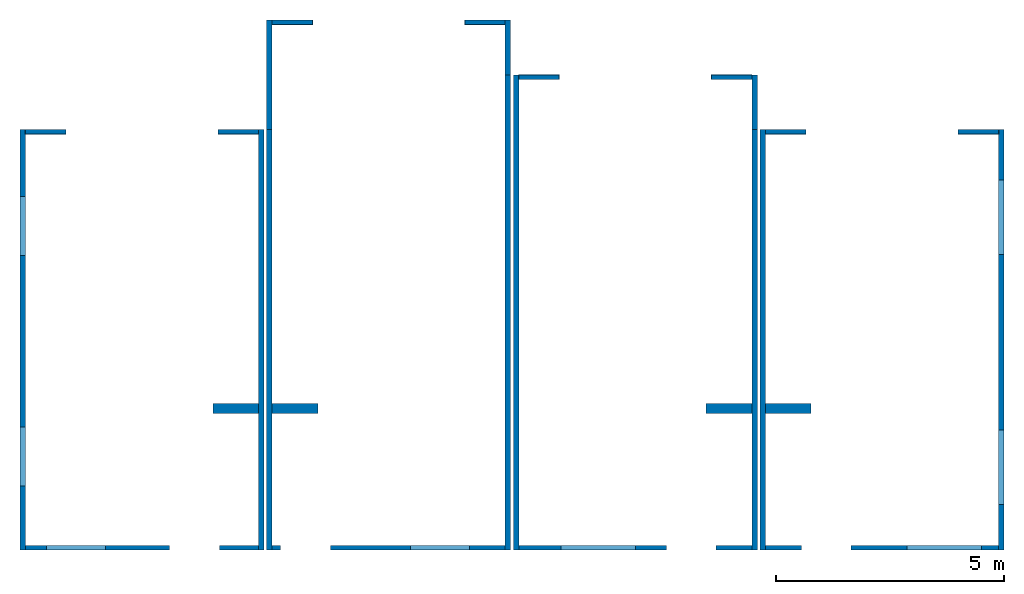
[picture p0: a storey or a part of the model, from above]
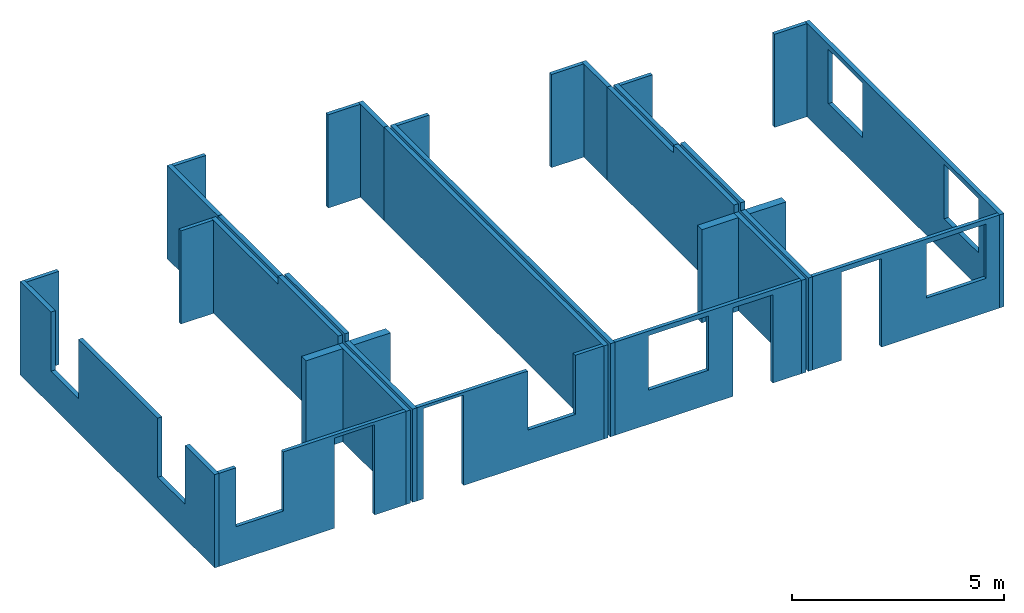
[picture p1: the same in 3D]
Properties of the parts of a building model (IFC2X3)

# File
Description: ViewDefinition [CoordinationView_V2.0]
File name: Voorbeeldproject Aanlevering BIM calduran_v2.ifc (Edited by simplebim 6.1 SR4)
Time: 2021-08-24T09:26:27
Written by: The EXPRESS Data Manager Version 5.02.0100.07 : 28 Aug 2013
Made in: 20190412_1200(x64) - Exporter 20.3.1.0 - Alternate UI 20.3.1.0 .Edited by BimVison - IFC Split

# IfcProject, 0001
LongName: Project Name; Phase: Project Status

# IfcSite, Harderwijk
RefLatitude: 42, 21, 29, 879998; RefLongitude: -71, -3, -37, -79998; RefElevation: 0 mm
ePset_ModelInfo - ModelName: Voorbeeldproject Aanlevering BIM calduran_v2.ifc; Timestamp: 2021-08-24T09:26:27
Text - TemplateVersie: bt_revit_template.rte : 20-06-2019 R2016 ©RB
Identity Data - Building Name: 763_Blok 01
Other - SiteName: Harderwijk; Category: Project Information; Project Number: 4 woningen; Client Name: Calduran b.v.; Project Address: 4 woningen te Harderwijk; Extensions.Parameters: n.v.t.; Project Issue Date: n.v.t.; Project Name: n.v.t.
Pset_ProductRequirements - Category: Project Information

# IfcBuilding
ePset_ModelInfo - ModelName: Voorbeeldproject Aanlevering BIM calduran_v2.ifc; Timestamp: 2021-08-24T09:26:27
Pset_BuildingCommon - NumberOfStoreys: 4
Text - TemplateVersie: bt_revit_template.rte : 20-06-2019 R2016 ©RB
Identity Data - Building Name: 763_Blok 01
Other - SiteName: Harderwijk; Category: Project Information; Project Number: 4 woningen; Client Name: Calduran b.v.; Project Address: 4 woningen te Harderwijk; Project Name: n.v.t.; Extensions.Parameters: n.v.t.; Project Issue Date: n.v.t.
Pset_ProductRequirements - Category: Project Information

# IfcBuildingStorey: Level:8mm Head (3)
ePset_ModelInfo - ModelName: Voorbeeldproject Aanlevering BIM calduran_v2.ifc; Timestamp: 2021-08-24T09:26:27
Dimensions - Computation Height: 0 mm
Identity Data(Type) - Type Name: hulp-level tbv Vloerpeil Niveau
Identity Data - Building Story: yes; Structural: no
Graphics(Type) - Color: 255; Symbol at End 1 Default: no; Symbol at End 2 Default: no; Line Weight: 1; Line Pattern: bt_hoogtelijn; Symbol: bt_hoogtelijnen: Hoogtemaat_Boven
Constraints(Type) - Elevation Base: Project Base Point
Pset_ProductRequirements - Category: Levels
Other(Type) - Category: Levels; Family Name: Level
Other - Family: Level: hulp-level tbv Vloerpeil Niveau; Family and Type: Level: hulp-level tbv Vloerpeil Niveau; Type: Level: hulp-level tbv Vloerpeil Niveau; Type Id: Level: hulp-level tbv Vloerpeil Niveau; Category: Levels
Name | LongName = Pset_AirSideSystemInformation, Name = Identity Data, Name = Pset_ProductRequirements, Name | Elevation (mm) = Constraints, Elevation (mm)
00 begane grond | 00 begane grond | 0
01 eerste verdieping | 01 eerste verdieping | 2920
02 tweede verdieping | 02 tweede verdieping | 5840

# IfcGrid (3)
ePset_ModelInfo - ModelName: Voorbeeldproject Aanlevering BIM calduran_v2.ifc; Timestamp: 2021-08-24T09:26:27
Name | In
 | 01 eerste verdieping
 | 00 begane grond
 | 02 tweede verdieping

# IfcOpeningElement: Opening (57)
ePset_ModelInfo - ModelName: Voorbeeldproject Aanlevering BIM calduran_v2.ifc; Timestamp: 2021-08-24T09:26:27
Name (Basic Wall:...) | In
2 x 21_kalkzandsteen element_CS12_100mm:1181608 | 00 begane grond
2 x 21_kalkzandsteen element_CS12_120mm:1090852 | 01 eerste verdieping
2 x 21_kalkzandsteen element_CS12_100mm:1182037 | 01 eerste verdieping
8 x 22_kalkzandsteen element_CS12_120mm:463458 | 00 begane grond | Classification: 22.22 binnenwanden; constructief, spouwwanden (NL/SfB)
2 x 21_kalkzandsteen element_CS12_120mm:1090762 | 00 begane grond
2 x 21_kalkzandsteen element_CS12_120mm:1090776 | 00 begane grond
8 x 22_kalkzandsteen element_CS12_120mm:463458 | 01 eerste verdieping | Classification: 22.22 binnenwanden; constructief, spouwwanden (NL/SfB)
2 x 21_kalkzandsteen element_CS12_100mm:1179562 | 00 begane grond
2 x 21_kalkzandsteen element_CS12_120mm:1090848 | 01 eerste verdieping
22_kalkzandsteen element_CS12_120mm:463458 | 02 tweede verdieping | Classification: 22.22 binnenwanden; constructief, spouwwanden (NL/SfB)
2 x 21_kalkzandsteen element_CS12_100mm:1182137 | 00 begane grond
21_kalkzandsteen element_CS12_120mm:1091307 | 02 tweede verdieping
2 x 21_kalkzandsteen element_CS12_100mm:1180744 | 01 eerste verdieping
21_kalkzandsteen element_CS12_100mm:1179981 | 00 begane grond
2 x 21_kalkzandsteen element_CS12_100mm:1180970 | 01 eerste verdieping
2 x 21_kalkzandsteen element_CS12_100mm:1181490 | 01 eerste verdieping
2 x 21_kalkzandsteen element_CS12_100mm:1181492 | 01 eerste verdieping
21_kalkzandsteen element_CS12_100mm:1181610 | 00 begane grond
2 x 21_kalkzandsteen element_CS12_100mm:1181998 | 01 eerste verdieping
21_kalkzandsteen element_CS12_100mm:1182139 | 00 begane grond
2 x 21_kalkzandsteen element_CS12_100mm:1182144 | 00 begane grond
21_kalkzandsteen element_CS12_100mm:1182146 | 00 begane grond
2 x 21_kalkzandsteen element_CS12_100mm:1182415 | 01 eerste verdieping
21_kalkzandsteen element_CS12_100mm:1182474 | 01 eerste verdieping
21_kalkzandsteen element_CS12_100mm:1183339 | 02 tweede verdieping
21_kalkzandsteen element_CS12_100mm:1184081 | 02 tweede verdieping
21_kalkzandsteen element_CS12_100mm:1179616 | 02 tweede verdieping | Classification: 21.12 buitenwanden; niet constructief, spouwwanden (NL/SfB)
21_kalkzandsteen element_CS12_100mm:1184943 | 02 tweede verdieping

# IfcWallStandardCase: 21_kalkzandsteen element_CS12_100mm (19)
Type - PredefinedType: STANDARD; Material: kalkzandsteen_CS12 100 mm
Type - Analytical Properties(Type) - Absorptance: 0.1; Roughness: 1
Type - Construction(Type) - Function: Exterior; Width: 100 mm; Wrapping at Inserts: Do not wrap
Type - Graphics(Type) - Coarse Scale Fill Color: 0; Coarse Scale Fill Pattern: Kalkzandsteen
Type - Identity Data(Type) - Assembly Code: 21.12; Assembly Description: buitenwanden; niet constructief, spouwwanden; Description: kalkzandsteen d=100 CS12; FireRatingR: 0 min.; LoadBearing: no; Sterkteklasse: CS12; Type Mark: KZS 100 (CS12); Type Name: 21_kalkzandsteen element_CS12_100mm; Type Comments: niet dragend
Type - Materials and Finishes(Type) - Structural Material: kalkzandsteen_CS12
Type - Other(Type) - Category: Walls; Family Name: Basic Wall
Classification: 21.12 buitenwanden; niet constructief, spouwwanden (NL/SfB)
ePset_ModelInfo - ModelName: Voorbeeldproject Aanlevering BIM calduran_v2.ifc; Timestamp: 2021-08-24T09:26:27
Pset_WallCommon - Reference: 21_kalkzandsteen element_CS12_100mm; LoadBearing: no; IsExternal: yes; ExtendToStructure: no
Phasing - Phase Created: 2. nieuwbouw
Pset_ElementShading - Roughness: 304.8 mm
Pset_QuantityTakeOff - Reference: 21_kalkzandsteen element_CS12_100mm
Constraints - Base Offset: -70 mm; Base Extension Distance: 0 mm; Base is Attached: no; Related to Mass: no; Room Bounding: yes; Top Extension Distance: 0 mm; Top is Attached: no; Location Line: Core Face: Exterior
Identity Data - IsExternal: yes
Other - Type Id: Basic Wall: 21_kalkzandsteen element_CS12_100mm; Family and Type: Basic Wall: 21_kalkzandsteen element_CS12_100mm; Type: Basic Wall: 21_kalkzandsteen element_CS12_100mm; Family: Basic Wall: 21_kalkzandsteen element_CS12_100mm; Category: Walls
Pset_ProductRequirements - Category: Walls
Structural - Structural: yes; Enable Analytical Model: yes; Structural Usage: Bearing; Rebar Cover - Other Faces: Rebar Cover Settings: Rebar Cover 1; Rebar Cover - Exterior Face: Rebar Cover Settings: Rebar Cover 1; Rebar Cover - Interior Face: Rebar Cover Settings: Rebar Cover 1
Calduran - Naam: Basic Wall: 21_kalkzandsteen element_CS12_100mm; Sterkteklasse: CS12; NL-Sfb omschrijving: buitenwanden; niet constructief, spouwwanden; NL-Sfb: 21.12; IsExternal: yes; LoadBearing: yes; Material: kalkzandsteen_CS12; Breedte: 100 mm
Pset_ReinforcementBarPitchOfWall - Description: kalkzandsteen d=100 CS12
Pset_Draughting - Red: 255; Green: 248; Blue: 220
BaseQuantities - Width: 100 mm
Name (Basic Wall:21_kalkzandsteen element_CS12_100mm:...) | In | Dimensions, Length (mm) = Lengte (mm) = BaseQuantities, Length (mm) | Dimensions, Volume (m3) = Calduran, Volume (m3) = NetVolume (m3) | Area (mm2) = Oppervlak (mm2) = NetSideArea (mm2) | Top Offset (mm) | Unconnected Height (mm) = Hoogte (mm) | Base Constraint = Top Constraint = Level | Identity Data, Bouwlaag = Calduran, Bouwlaag | GrossFootprintArea (mm2) | Height (mm)
1181608 | 00 begane grond | 5100 | 0.839766 | 8397660 | 2620 | 2690 | Level: 00 begane grond | 00 begane grond | 510000 | 2690
1182037 | 01 eerste verdieping | 5100 | 0.958892 | 9588920 | 2620 | 2690 | Level: 01 eerste verdieping | 01 eerste verdieping | 510000 | 2690
1179562 | 00 begane grond | 5100 | 0.86819 | 8681900 | 2620 | 2690 | Level: 00 begane grond | 00 begane grond | 510000 | 2690
1182137 | 00 begane grond | 5100 | 0.839766 | 8397660 | 2620 | 2690 | Level: 00 begane grond | 00 begane grond | 510000 | 2690
1180744 | 01 eerste verdieping | 5100 | 0.922284 | 9222840 | 2620 | 2690 | Level: 01 eerste verdieping | 01 eerste verdieping | 510000 | 2690
1179981 | 00 begane grond | 5100 | 0.475054 | 4750540 | 2620 | 2690 | Level: 00 begane grond | 00 begane grond | 510000 | 2690
1180970 | 01 eerste verdieping | 5100 | 0.958892 | 9588920 | 2620 | 2690 | Level: 01 eerste verdieping | 01 eerste verdieping | 510000 | 2690
1181490 | 01 eerste verdieping | 5100 | 0.8754 | 8754000 | 2620 | 2690 | Level: 01 eerste verdieping | 01 eerste verdieping | 510000 | 2690
1181492 | 01 eerste verdieping | 5100 | 0.958892 | 9588920 | 2620 | 2690 | Level: 01 eerste verdieping | 01 eerste verdieping | 510000 | 2690
1181610 | 00 begane grond | 5100 | 0.475054 | 4750540 | 2620 | 2690 | Level: 00 begane grond | 00 begane grond | 510000 | 2690
1181998 | 01 eerste verdieping | 5100 | 0.958892 | 9588920 | 2620 | 2690 | Level: 01 eerste verdieping | 01 eerste verdieping | 510000 | 2690
1182139 | 00 begane grond | 5100 | 0.475054 | 4750540 | 2620 | 2690 | Level: 00 begane grond | 00 begane grond | 510000 | 2690
1182144 | 00 begane grond | 5100 | 0.86819 | 8681900 | 2620 | 2690 | Level: 00 begane grond | 00 begane grond | 510000 | 2690
1182146 | 00 begane grond | 5100 | 0.475054 | 4750540 | 2620 | 2690 | Level: 00 begane grond | 00 begane grond | 510000 | 2690
1182415 | 01 eerste verdieping | 5100 | 1.06634 | 10663400 | 2620 | 2690 | Level: 01 eerste verdieping | 01 eerste verdieping | 510000 | 2690
1182474 | 01 eerste verdieping | 5100 | 1.0047 | 10047000 | 2620 | 2690 | Level: 01 eerste verdieping | 02 tweede verdieping | 510000 | 2690
1183339 | 02 tweede verdieping | 5100 | 1.05306 | 10530583 | 4090 | 4160 | Level: 02 tweede verdieping | 02 tweede verdieping | 510000 | 4154.26
1184081 | 02 tweede verdieping | 5100 | 0.981285 | 9812849 | 4090 | 4160 | Level: 02 tweede verdieping | 02 tweede verdieping | 510000 | 4154.26
1184943 | 02 tweede verdieping | 3103 | 0.707432 | 7074316 | 4090 | 4160 | Level: 02 tweede verdieping | 02 tweede verdieping | 310300 | 4186.14

# IfcWallStandardCase: 21_kalkzandsteen element_CS12_120mm (9)
Type - PredefinedType: STANDARD; Material: kalkzandsteen_CS12 120 mm
Type - Analytical Properties(Type) - Absorptance: 0.1; Roughness: 1
Type - Construction(Type) - Function: Exterior; Width: 120 mm; Wrapping at Inserts: Do not wrap
Type - Graphics(Type) - Coarse Scale Fill Color: 0; Coarse Scale Fill Pattern: Kalkzandsteen
Type - Identity Data(Type) - Assembly Code: 21.22; Assembly Description: buitenwanden; constructief, spouwwanden; Description: kalkzandsteen d=120 CS12; FireRatingR: 0 min.; LoadBearing: yes; Sterkteklasse: CS12; Type Mark: KZS 120 (CS12); Type Name: 21_kalkzandsteen element_CS12_120mm
Type - Materials and Finishes(Type) - Structural Material: kalkzandsteen_CS12
Type - Other(Type) - Category: Walls; Family Name: Basic Wall
Classification: 21.22 buitenwanden; constructief, spouwwanden (NL/SfB)
ePset_ModelInfo - ModelName: Voorbeeldproject Aanlevering BIM calduran_v2.ifc; Timestamp: 2021-08-24T09:26:27
Pset_ReinforcementBarPitchOfWall - Description: kalkzandsteen d=120 CS12
Phasing - Phase Created: 2. nieuwbouw
Constraints - Base Offset: -70 mm; Base Extension Distance: 0 mm; Base is Attached: no; Related to Mass: no; Room Bounding: yes; Top Extension Distance: 0 mm; Top is Attached: no
Pset_ElementShading - Roughness: 304.8 mm
Pset_WallCommon - Reference: 21_kalkzandsteen element_CS12_120mm; LoadBearing: yes; IsExternal: yes; ExtendToStructure: no
Other - Family and Type: Basic Wall: 21_kalkzandsteen element_CS12_120mm; Type: Basic Wall: 21_kalkzandsteen element_CS12_120mm; Type Id: Basic Wall: 21_kalkzandsteen element_CS12_120mm; Family: Basic Wall: 21_kalkzandsteen element_CS12_120mm; Category: Walls
Pset_ProductRequirements - Category: Walls
Pset_QuantityTakeOff - Reference: 21_kalkzandsteen element_CS12_120mm
Structural - Structural: yes; Enable Analytical Model: yes; Structural Usage: Bearing; Rebar Cover - Other Faces: Rebar Cover Settings: Rebar Cover 1; Rebar Cover - Exterior Face: Rebar Cover Settings: Rebar Cover 1; Rebar Cover - Interior Face: Rebar Cover Settings: Rebar Cover 1
Calduran - Sterkteklasse: CS12; Naam: Basic Wall: 21_kalkzandsteen element_CS12_120mm; IsExternal: yes; LoadBearing: yes; Material: kalkzandsteen_CS12; Breedte: 120 mm; NL-Sfb: 21.22; NL-Sfb omschrijving: buitenwanden; constructief, spouwwanden
Pset_Draughting - Red: 255; Green: 248; Blue: 220
BaseQuantities - Width: 120 mm
Name (Basic Wall:21_kalkzandsteen element_CS12_120mm:...) | In | Dimensions, Volume (m3) = Calduran, Volume (m3) = NetVolume (m3) | Dimensions, Length (mm) = Lengte (mm) = BaseQuantities, Length (mm) | Area (mm2) = Oppervlak (mm2) = NetSideArea (mm2) | Location Line | Top Offset (mm) | Unconnected Height (mm) = Hoogte (mm) | Base Constraint = Top Constraint = Level | IsExternal | Identity Data, Bouwlaag = Calduran, Bouwlaag | GrossFootprintArea (mm2) | Height (mm)
1090750 | 00 begane grond | 0.38736 | 1200 | 3228000 | Wall Centerline | 2620 | 2690 | Level: 00 begane grond | yes | 00 begane grond | 144000 | 2690
1090852 | 01 eerste verdieping | 2.43022 | 9200 | 20251840 | Wall Centerline | 2620 | 2690 | Level: 01 eerste verdieping | yes | 01 eerste verdieping | 1104000 | 2690
1090762 | 00 begane grond | 2.35482 | 9200 | 19623520 | Wall Centerline | 2620 | 2690 | Level: 00 begane grond | yes | 00 begane grond | 1104000 | 2690
1090776 | 00 begane grond | 2.44107 | 9200 | 20342280 | Wall Centerline | 2620 | 2690 | Level: 00 begane grond | yes | 00 begane grond | 1104000 | 2690
1090848 | 01 eerste verdieping | 2.33328 | 9200 | 19444000 | Wall Centerline | 2620 | 2690 | Level: 01 eerste verdieping | yes | 01 eerste verdieping | 1104000 | 2690
1091307 | 02 tweede verdieping | 2.32044 | 9200 | 19336996 | Wall Centerline | 5160 | 5230 | Level: 02 tweede verdieping | yes | 02 tweede verdieping | 1104000 | 4223.55
1194969 | 00 begane grond | 0.77472 | 2400 | 6456000 | Core Face: Exterior | 2620 | 2690 | Level: 00 begane grond |  | 00 begane grond | 288000 | 2690
1195436 | 00 begane grond | 0.38736 | 1200 | 3228000 | Wall Centerline | 2620 | 2690 | Level: 00 begane grond | yes | 00 begane grond | 144000 | 2690
1252887 | 02 tweede verdieping | 0.269636 | 1175.19 | 2246966 | Core Face: Exterior | 1842 | 1912 | Level: 02 tweede verdieping |  |  | 141023 | 1912

# IfcWallStandardCase: 22_kalkzandsteen element_CS12_120mm (18)
Type - PredefinedType: STANDARD; Material: kalkzandsteen_CS12 120 mm
Type - Analytical Properties(Type) - Absorptance: 0.1; Roughness: 1
Type - Construction(Type) - Function: Exterior; Width: 120 mm; Wrapping at Inserts: Do not wrap
Type - Graphics(Type) - Coarse Scale Fill Color: 0; Coarse Scale Fill Pattern: Kalkzandsteen
Type - Identity Data(Type) - Assembly Code: 22.22; Assembly Description: binnenwanden; constructief, spouwwanden; Description: kalkzandsteen d=120 CS12; FireRatingR: 0 min.; LoadBearing: yes; Sterkteklasse: CS12; Type Mark: KZS 120 (CS12); Type Name: 22_kalkzandsteen element_CS12_120mm
Type - Materials and Finishes(Type) - Structural Material: kalkzandsteen_CS12
Type - Other(Type) - Category: Walls; Family Name: Basic Wall
Classification: 22.22 binnenwanden; constructief, spouwwanden (NL/SfB)
ePset_ModelInfo - ModelName: Voorbeeldproject Aanlevering BIM calduran_v2.ifc; Timestamp: 2021-08-24T09:26:27
Pset_ReinforcementBarPitchOfWall - Description: kalkzandsteen d=120 CS12
Phasing - Phase Created: 2. nieuwbouw
Constraints - Base Offset: -70 mm; Location Line: Wall Centerline; Base Extension Distance: 0 mm; Base is Attached: no; Related to Mass: no; Room Bounding: yes; Top Extension Distance: 0 mm; Top is Attached: no
Pset_WallCommon - LoadBearing: yes; IsExternal: no; ExtendToStructure: no; Reference: 22_kalkzandsteen element_CS12_120mm
Pset_ElementShading - Roughness: 304.8 mm
Calduran - NL-Sfb: 22.22; Sterkteklasse: CS12; Naam: Basic Wall: 22_kalkzandsteen element_CS12_120mm; NL-Sfb omschrijving: binnenwanden; constructief, spouwwanden; LoadBearing: yes; IsExternal: no; Material: kalkzandsteen_CS12; Breedte: 120 mm
Pset_QuantityTakeOff - Reference: 22_kalkzandsteen element_CS12_120mm
Other - Family: Basic Wall: 22_kalkzandsteen element_CS12_120mm; Type Id: Basic Wall: 22_kalkzandsteen element_CS12_120mm; Type: Basic Wall: 22_kalkzandsteen element_CS12_120mm; Family and Type: Basic Wall: 22_kalkzandsteen element_CS12_120mm; Category: Walls
Pset_ProductRequirements - Category: Walls
Structural - Structural: yes; Enable Analytical Model: yes; Structural Usage: Bearing; Rebar Cover - Other Faces: Rebar Cover Settings: Rebar Cover 1; Rebar Cover - Exterior Face: Rebar Cover Settings: Rebar Cover 1; Rebar Cover - Interior Face: Rebar Cover Settings: Rebar Cover 1
Identity Data - IsExternal: no
Pset_Draughting - Red: 255; Green: 248; Blue: 220
BaseQuantities - Width: 120 mm
Name (Basic Wall:22_kalkzandsteen element_CS12_120mm:...) | In | Base Constraint = Top Constraint = Level | Top Offset (mm) | Unconnected Height (mm) = Hoogte (mm) | Calduran, Volume (m3) = Dimensions, Volume (m3) = NetVolume (m3) | Lengte (mm) = Dimensions, Length (mm) = BaseQuantities, Length (mm) | Oppervlak (mm2) = Area (mm2) = NetSideArea (mm2) | Calduran, Bouwlaag = Identity Data, Bouwlaag | GrossFootprintArea (mm2) | Height (mm)
1090844 | 01 eerste verdieping | Level: 01 eerste verdieping | 2620 | 2690 | 2.96976 | 9200 | 24748000 | 01 eerste verdieping | 1104000 | 2690
1090752 | 00 begane grond | Level: 00 begane grond | 2620 | 2690 | 3.35712 | 10400 | 27976000 | 00 begane grond | 1248000 | 2690
1091175 | 02 tweede verdieping | Level: 02 tweede verdieping | 5160 | 5230 | 2.53221 | 9200 | 21101724 | 02 tweede verdieping | 1104000 | 4223.59
1090838 | 01 eerste verdieping | Level: 01 eerste verdieping | 2620 | 2690 | 2.96976 | 9200 | 24748000 | 01 eerste verdieping | 1104000 | 2690
1090754 | 00 begane grond | Level: 00 begane grond | 2620 | 2690 | 3.04842 | 9200 | 25403500 | 00 begane grond | 1104000 | 2920
1090756 | 00 begane grond | Level: 00 begane grond | 2620 | 2690 | 3.04842 | 9200 | 25403500 | 00 begane grond | 1104000 | 2920
1090758 | 00 begane grond | Level: 00 begane grond | 2620 | 2690 | 3.35712 | 10400 | 27976000 | 00 begane grond | 1248000 | 2690
1090760 | 00 begane grond | Level: 00 begane grond | 2620 | 2690 | 3.04842 | 9200 | 25403500 | 00 begane grond | 1104000 | 2920
1090836 | 01 eerste verdieping | Level: 01 eerste verdieping | 2620 | 2690 | 3.04842 | 9200 | 25403500 | 01 eerste verdieping | 1104000 | 2920
1090840 | 01 eerste verdieping | Level: 01 eerste verdieping | 2620 | 2690 | 3.04842 | 9200 | 25403500 | 01 eerste verdieping | 1104000 | 2920
1090842 | 01 eerste verdieping | Level: 01 eerste verdieping | 2620 | 2690 | 3.04842 | 9200 | 25403500 | 01 eerste verdieping | 1104000 | 2920
1090846 | 01 eerste verdieping | Level: 01 eerste verdieping | 2620 | 2690 | 3.04842 | 9200 | 25403500 | 01 eerste verdieping | 1104000 | 2920
1091219 | 02 tweede verdieping | Level: 02 tweede verdieping | 5160 | 5230 | 2.70359 | 9200 | 22529892 | 02 tweede verdieping | 1104000 | 4223.55
1091241 | 02 tweede verdieping | Level: 02 tweede verdieping | 5160 | 5230 | 2.53216 | 9200 | 21101356 | 02 tweede verdieping | 1104000 | 4223.55
1091263 | 02 tweede verdieping | Level: 02 tweede verdieping | 5160 | 5230 | 2.53221 | 9200 | 21101724 | 02 tweede verdieping | 1104000 | 4223.59
1091285 | 02 tweede verdieping | Level: 02 tweede verdieping | 5160 | 5230 | 2.5316 | 9200 | 21096689 | 02 tweede verdieping | 1104000 | 4223.05
1159302 | 02 tweede verdieping | Level: 02 tweede verdieping | 5160 | 5230 | 2.53221 | 9200 | 21101724 | 02 tweede verdieping | 1104000 | 4223.59
1200641 | 00 begane grond | Level: 00 begane grond | 2620 | 2690 | 3.04842 | 9200 | 25403500 | 00 begane grond | 1104000 | 2920

# IfcWallStandardCase: 22_kalkzandsteen element_CS36_214mm (8)
Type - PredefinedType: STANDARD; Material: kalkzandsteen_CS36 214 mm
Type - Analytical Properties(Type) - Absorptance: 0.1; Roughness: 1
Type - Construction(Type) - Function: Interior; Width: 214 mm; Wrapping at Inserts: Do not wrap
Type - Graphics(Type) - Coarse Scale Fill Color: 0; Coarse Scale Fill Pattern: Kalkzandsteen
Type - Identity Data(Type) - Assembly Code: 22.21; Assembly Description: binnenwanden; constructief, massieve wanden; Description: kalkzandsteen d=214 CS36; LoadBearing: yes; Sterkteklasse: CS36; Type Mark: KZS 214 (CS36); Type Name: 22_kalkzandsteen element_CS36_214mm; Fire Rating: 0 min.; Type Comments: tbv stabiliteit
Type - Materials and Finishes(Type) - Structural Material: kalkzandsteen_CS36
Type - Other(Type) - Category: Walls; Family Name: Basic Wall
Classification: 22.21 binnenwanden; constructief, massieve wanden (NL/SfB)
ePset_ModelInfo - ModelName: Voorbeeldproject Aanlevering BIM calduran_v2.ifc; Timestamp: 2021-08-24T09:26:27
Calduran - NL-Sfb: 22.21; Material: kalkzandsteen_CS36; LoadBearing: yes; IsExternal: no; FireRatingR: 0 min.; NL-Sfb omschrijving: binnenwanden; constructief, massieve wanden; Breedte: 214 mm; Hoogte: 2690 mm; Sterkteklasse: CS36; Naam: Basic Wall: 22_kalkzandsteen element_CS36_214mm
Pset_ReinforcementBarPitchOfWall - Description: kalkzandsteen d=214 CS36
Phasing - Phase Created: 2. nieuwbouw
Constraints - Base Offset: -70 mm; Location Line: Wall Centerline; Base Extension Distance: 0 mm; Base is Attached: no; Related to Mass: no; Room Bounding: yes; Top Extension Distance: 0 mm; Top is Attached: no; Top Offset: 2620 mm; Unconnected Height: 2690 mm
Pset_ConcreteElementGeneral - FireRating: 0 min.
Pset_ElementShading - Roughness: 304.8 mm
Pset_WallCommon - LoadBearing: yes; IsExternal: no; ExtendToStructure: no; FireRating: 0 min.; Reference: 22_kalkzandsteen element_CS36_214mm
Identity Data - IsExternal: no
Other - Category: Walls; Family: Basic Wall: 22_kalkzandsteen element_CS36_214mm; Type Id: Basic Wall: 22_kalkzandsteen element_CS36_214mm; Type: Basic Wall: 22_kalkzandsteen element_CS36_214mm; Family and Type: Basic Wall: 22_kalkzandsteen element_CS36_214mm
Pset_QuantityTakeOff - Reference: 22_kalkzandsteen element_CS36_214mm
Pset_ProductRequirements - Category: Walls
Structural - Structural: yes; Enable Analytical Model: yes; Structural Usage: Bearing; Rebar Cover - Other Faces: Rebar Cover Settings: Rebar Cover 1; Rebar Cover - Exterior Face: Rebar Cover Settings: Rebar Cover 1; Rebar Cover - Interior Face: Rebar Cover Settings: Rebar Cover 1
Pset_Draughting - Red: 255; Green: 248; Blue: 220
BaseQuantities - Width: 214 mm; Height: 2690 mm
Name (Basic Wall:22_kalkzandsteen element_CS36_214mm:...) | In | Calduran, Volume (m3) = Dimensions, Volume (m3) = NetVolume (m3) | Calduran, Bouwlaag = Identity Data, Bouwlaag | Lengte (mm) = Dimensions, Length (mm) = BaseQuantities, Length (mm) | Oppervlak (mm2) = Area (mm2) = NetSideArea (mm2) | Level = Base Constraint = Top Constraint | GrossFootprintArea (mm2)
1090766 | 00 begane grond | 0.57566 | 00 begane grond | 1000 | 2690000 | Level: 00 begane grond | 214000
1090768 | 00 begane grond | 0.57566 | 00 begane grond | 1000 | 2690000 | Level: 00 begane grond | 214000
1093607 | 00 begane grond | 0.57566 | 00 begane grond | 1000 | 2690000 | Level: 00 begane grond | 214000
1093609 | 00 begane grond | 0.57566 | 00 begane grond | 1000 | 2690000 | Level: 00 begane grond | 214000
1101353 | 01 eerste verdieping | 0.615956 | 01 eerste verdieping | 1070 | 2878300 | Level: 01 eerste verdieping | 228980
1101355 | 01 eerste verdieping | 0.615956 | 01 eerste verdieping | 1070 | 2878300 | Level: 01 eerste verdieping | 228980
1101359 | 01 eerste verdieping | 0.615956 | 01 eerste verdieping | 1070 | 2878300 | Level: 01 eerste verdieping | 228980
1101361 | 01 eerste verdieping | 0.615956 | 01 eerste verdieping | 1070 | 2878300 | Level: 01 eerste verdieping | 228980
